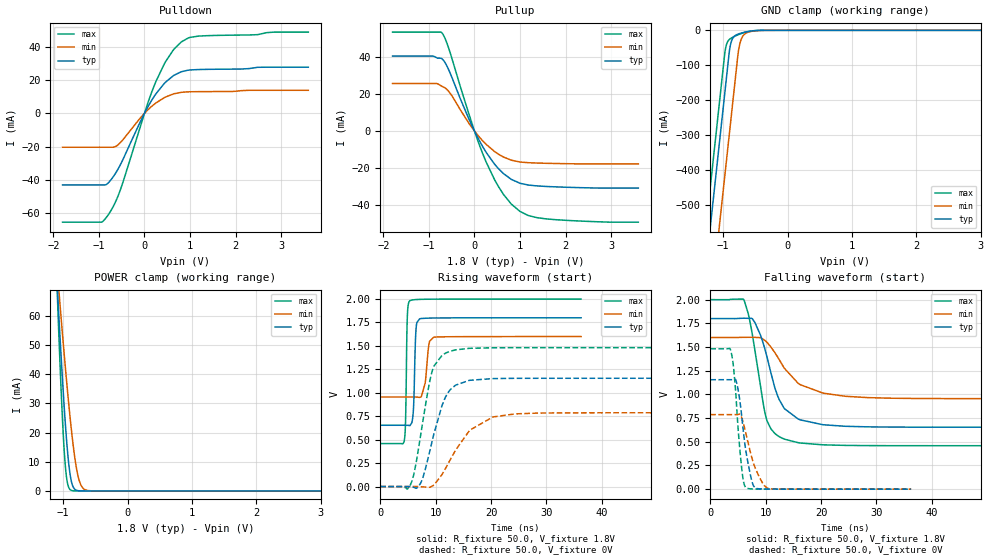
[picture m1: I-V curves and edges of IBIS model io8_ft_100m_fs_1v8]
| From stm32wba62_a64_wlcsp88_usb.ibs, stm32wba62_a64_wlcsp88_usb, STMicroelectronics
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[Model]   io8_ft_100m_fs_1v8
Model_type I/O
Polarity   Non-Inverting
Enable   Active-Low
| CAP_THRESHOLD on pad IOFT is "UDTCAPC" :
| Rising=30.0% of vddiom   Falling=70.0% of vddiom
| C_comp min and max val. don't necessarily correlate with the min and max pvt
| but are the smallest and greatest pad capacitance found.
| var   typ   min   max
C_comp   3.36302pF  3.33592pF  3.49657pF
|C_comp_pullup   1.98084pF  1.87511pF  2.12869pF
|C_comp_pulldown   1.38217pF  1.46081pF  1.36788pF
Vinl = 800.0mV
Vinh = 1.0V
Vmeas = 900.0mV   | Reference voltage for timing measurements
Cref  = 50.0pF   | Timing specification test load capacitance value
Rref  = 1.0MOhm   | Timing specification test load resistance value
Vref  = 990.0mV   | Timing specification test load voltage
[Model Spec]
| TIME_THRESHOLD on pin ZIV11 is "CMOS" :
| Rising=50.0% of vdd   Falling=50.0% of vdd
Vinl 702.50000mV 626.50000mV 788.50000mV
Vinh 1.09050V 959.50000mV 1.19650V
| variable   typ   min   max
[Temperature Range] 25.0 140.0 -40.0
| variable   typ   min   max
[Voltage Range] 1.8V 1.6V 2.0V
| variable   typ   min   max
[POWER Clamp Reference] 1.8V 1.6V 2.0V
| variable   typ   min   max
[GND Clamp Reference] 0V 0V 0V
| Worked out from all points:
|   slope of the pulldown table from 0 to 0.27 V, typ, clamps not added: 21.9 ohm
|   slope of the pullup table from 0 to 0.27 V, typ, clamps not added: 22.6 ohm
|   GND clamp passes 1 mA (typ) near -0.51 V on its own axis
|   POWER clamp passes 1 mA (typ) near -0.83 V on its own axis
|   rising waveform, R_fixture 50.0, V_fixture 1.8V: 20-80 % time 322ps typ, 667ps min, 236ps max; typ from 0.654 V to 1.8 V
|   falling waveform, R_fixture 50.0, V_fixture 1.8V: 20-80 % time 3.66ns typ, 5.8ns min, 2.61ns max; typ from 1.8 V to 0.654 V
|   rising waveform, R_fixture 50.0, V_fixture 0V: 20-80 % time 3.23ns typ, 5.55ns min, 2.57ns max; typ from 0 V to 1.16 V
|   falling waveform, R_fixture 50.0, V_fixture 0V: 20-80 % time 1.6ns typ, 2.36ns min, 1.18ns max; typ from 1.16 V to 0 V
[POWER Clamp]
-1.8V     396.4mA    285.5mA    556.9mA
-1.09V    69.42mA    75.17mA    67.14mA
-1.08V    65.31mA    72.42mA    61.23mA
-1.06V    57.23mA    66.98mA    49.77mA
-1.02V    41.75mA    56.3mA     28.91mA
-980mV    27.6mA     45.97mA    12.6mA
-940mV    15.59mA    36.11mA    3.485mA
-880mV    4.091mA    22.61mA    262.5uA
-820mV    594.6uA    11.56mA    16.39uA
-760mV    69.41uA    4.321mA    1.008uA
-630mV    611.2nA    197uA      2.486nA
3.6V      0A         0A         0A
[GND Clamp]
-1.8V     -1.583A    -1.82A     -1.468A
-1.43V    -953.9mA   -1.191A    -839.3mA
-1.24V    -630.9mA   -867.8mA   -516.3mA
-1.05V    -307.9mA   -544.8mA   -193.3mA
-980mV    -188.9mA   -425.8mA   -74.3mA
-950mV    -137.9mA   -374.8mA   -41.62mA
-890mV    -44.57mA   -272.8mA   -24.11mA
-800mV    -13.55mA   -119.8mA   -15.31mA
-760mV    -10.3mA    -56.67mA   -12.19mA
-720mV    -7.957mA   -26.08mA   -9.381mA
-540mV    -1.564mA   -2.435mA   -1.367mA
3.6V      1.281nA    268.1nA    531.2pA
| variable   typ   min   max
[Pullup Reference] 1.8V 1.6V 2.0V
| variable   typ   min   max
[Pulldown Reference] 0V 0V 0V
[Pullup]
-1.8V     40.39mA    25.65mA    53.35mA
-840mV    39.66mA    25.65mA    53.35mA
-700mV    38.63mA    23.9mA     52.42mA
-560mV    32.64mA    21.16mA    44.13mA
0V        593fA      222.5pA    3.42fA
260mV     -11.6mA    -7.233mA   -16.88mA
440mV     -17.8mA    -11.01mA   -26.16mA
630mV     -22.78mA   -13.92mA   -33.91mA
1V        -28.15mA   -16.69mA   -43.34mA
1.18V     -29.09mA   -17.06mA   -45.52mA
1.6V      -29.9mA    -17.4mA    -47.4mA
3.6V      -30.74mA   -17.73mA   -49.13mA
[Pulldown]
-1.8V     -42.97mA   -20.34mA   -65.35mA
-940mV    -42.97mA   -20.34mA   -65.31mA
-780mV    -41.3mA    -20.34mA   -60.25mA
-650mV    -36.58mA   -20.1mA    -53.93mA
-530mV    -30.86mA   -17.55mA   -45.89mA
0V        3fA        0A         0A
250mV     11.67mA    6.208mA    19.03mA
460mV     18.64mA    9.755mA    30.89mA
630mV     22.5mA     11.58mA    37.88mA
810mV     24.97mA    12.61mA    42.87mA
1.18V     26.28mA    13mA       46.33mA
3.6V      27.68mA    13.83mA    48.76mA
[Ramp]
dV/dt_r 693.11029mV/3.20165ns 472.14877mV/5.25042ns 888.79248mV/2.57222ns
dV/dt_f 687.69291mV/3.59389ns 386.8465mV/5.49572ns 924.86465mV/2.61188ns
R_load = 50.0
| Removed startup time: 0s 0s 0s  .
| Removed end time: 36.25ns.
[Rising Waveform]
R_fixture   = 50.0
V_fixture   = 1.8V
V_fixture_min = 1.6V
V_fixture_max = 2.0V
0s        653.8mV    955.3mV    458.6mV
4.3ns     653.9mV    955.3mV    481.6mV
4.55ns    653.9mV    955.3mV    668.4mV
4.9ns     653.6mV    955.3mV    1.837V
5.35ns    649.8mV    955.3mV    1.984V
6ns       837.6mV    955.2mV    1.992V
6.5ns     1.71V      954.8mV    1.995V
7.1ns     1.789V     950.8mV    1.996V
9.65ns    1.798V     1.593V     1.999V
36.25ns   1.8V       1.6V       2V
| Removed startup time: 0s 0s 0s  .
| Removed end time: 199.25ns.
[Falling Waveform]
R_fixture   = 50.0
V_fixture   = 1.8V
V_fixture_min = 1.6V
V_fixture_max = 2.0V
0s        1.8V       1.6V       2V
6.05ns    1.804V     1.603V     1.999V
6.95ns    1.803V     1.603V     1.828V
8ns       1.763V     1.602V     1.486V
9.65ns    1.52V      1.578V     873.3mV
10.3ns    1.38V      1.546V     713.1mV
12.5ns    938.3mV    1.361V     552.4mV
16.25ns   731.3mV    1.102V     487.1mV
32.55ns   655.3mV    959.9mV    459mV
199.3ns   653.8mV    955.3mV    458.6mV
| Removed startup time: 0s 0s 0s  .
| Removed end time: 199.2ns.
[Rising Waveform]
R_fixture   = 50.0
V_fixture   = 0V
V_fixture_min = 0V
V_fixture_max = 0V
0s        4.66nV     149.2nV    3.397nV
5.35ns    -1.172mV   471.1nV    8.191mV
6.15ns    -10.56mV   27.35uV    156.5mV
7.35ns    44.58mV    -1.872mV   571.2mV
9.5ns     518mV      9.132mV    1.255V
11.75ns   952.7mV    190.1mV    1.422V
13.6ns    1.082V     389.2mV    1.458V
16.25ns   1.134V     604.6mV    1.475V
24.4ns    1.154V     775.1mV    1.481V
199.2ns   1.155V     786.9mV    1.481V
| Removed startup time: 0s 0s 0s  .
| Removed end time: 36.25ns.
[Falling Waveform]
R_fixture   = 50.0
V_fixture   = 0V
V_fixture_min = 0V
V_fixture_max = 0V
0s        1.155V     786.9mV    1.481V
3.7ns     1.155V     786.9mV    1.461V
4.25ns    1.155V     786.9mV    1.257V
4.9ns     1.086V     787mV      741mV
5.75ns    729.5mV    740.9mV    180.6mV
6.4ns     411.6mV    595.6mV    18.08mV
7.8ns     34.99mV    272.6mV    1.972mV
9.65ns    1.899mV    41.61mV    774.7uV
10.35ns   1.345mV    9.299mV    644.6uV
36.25ns   1.594uV    7.4uV      677.6nV
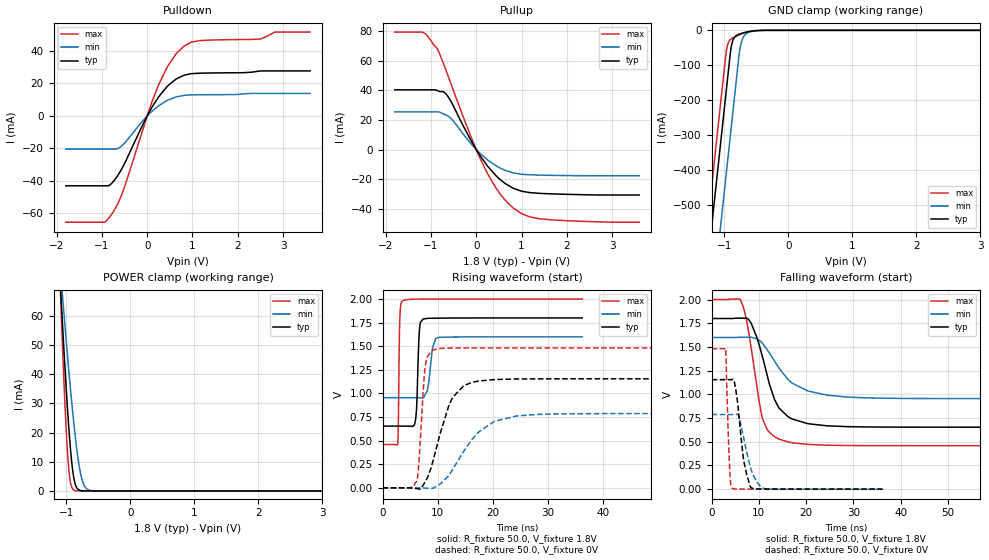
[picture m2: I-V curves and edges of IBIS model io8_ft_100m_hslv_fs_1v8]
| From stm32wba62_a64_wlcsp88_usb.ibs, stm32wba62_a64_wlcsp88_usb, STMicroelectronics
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[Model]   io8_ft_100m_hslv_fs_1v8
Model_type I/O
Polarity   Non-Inverting
Enable   Active-Low
| CAP_THRESHOLD on pad IOFT is "UDTCAPC" :
| Rising=30.0% of vddiom   Falling=70.0% of vddiom
| C_comp min and max val. don't necessarily correlate with the min and max pvt
| but are the smallest and greatest pad capacitance found.
| var   typ   min   max
C_comp   3.45851pF  3.43539pF  3.59268pF
|C_comp_pullup   2.05736pF  1.95438pF  2.20463pF
|C_comp_pulldown   1.40115pF  1.48101pF  1.38804pF
Vinl = 800.0mV
Vinh = 1.0V
Vmeas = 900.0mV   | Reference voltage for timing measurements
Cref  = 50.0pF   | Timing specification test load capacitance value
Rref  = 1.0MOhm   | Timing specification test load resistance value
Vref  = 990.0mV   | Timing specification test load voltage
[Model Spec]
| TIME_THRESHOLD on pin ZIV11 is "CMOS" :
| Rising=50.0% of vdd   Falling=50.0% of vdd
Vinl 702.50000mV 626.50000mV 788.50000mV
Vinh 1.09050V 959.50000mV 1.19650V
| variable   typ   min   max
[Temperature Range] 25.0 140.0 -40.0
| variable   typ   min   max
[Voltage Range] 1.8V 1.6V 2.0V
| variable   typ   min   max
[POWER Clamp Reference] 1.8V 1.6V 2.0V
| variable   typ   min   max
[GND Clamp Reference] 0V 0V 0V
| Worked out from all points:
|   slope of the pulldown table from 0 to 0.27 V, typ, clamps not added: 21.9 ohm
|   slope of the pullup table from 0 to 0.27 V, typ, clamps not added: 22.7 ohm
|   GND clamp passes 1 mA (typ) near -0.51 V on its own axis
|   POWER clamp passes 1 mA (typ) near -0.83 V on its own axis
|   rising waveform, R_fixture 50.0, V_fixture 1.8V: 20-80 % time 389ps typ, 756ps min, 202ps max; typ from 0.654 V to 1.8 V
|   falling waveform, R_fixture 50.0, V_fixture 1.8V: 20-80 % time 4.19ns typ, 6.65ns min, 2.95ns max; typ from 1.8 V to 0.654 V
|   rising waveform, R_fixture 50.0, V_fixture 0V: 20-80 % time 3.54ns typ, 6.08ns min, 949ps max; typ from 0 V to 1.16 V
|   falling waveform, R_fixture 50.0, V_fixture 0V: 20-80 % time 1.62ns typ, 2.33ns min, 588ps max; typ from 1.16 V to 0 V
[POWER Clamp]
-1.8V     396.4mA    285.5mA    556.9mA
-1.09V    69.42mA    75.17mA    67.14mA
-1.08V    65.31mA    72.42mA    61.23mA
-1.06V    57.23mA    66.98mA    49.77mA
-1.02V    41.75mA    56.3mA     28.91mA
-980mV    27.6mA     45.97mA    12.6mA
-940mV    15.59mA    36.11mA    3.485mA
-880mV    4.091mA    22.61mA    262.5uA
-820mV    594.6uA    11.56mA    16.39uA
-760mV    69.41uA    4.321mA    1.008uA
-630mV    611.3nA    197uA      2.478nA
3.6V      0A         0A         0A
[GND Clamp]
-1.8V     -1.583A    -1.82A     -1.468A
-1.43V    -953.9mA   -1.191A    -839.3mA
-1.24V    -630.9mA   -867.8mA   -516.3mA
-1.05V    -307.9mA   -544.8mA   -193.3mA
-980mV    -188.9mA   -425.8mA   -74.3mA
-950mV    -137.9mA   -374.8mA   -41.62mA
-890mV    -44.57mA   -272.8mA   -24.11mA
-800mV    -13.55mA   -119.8mA   -15.31mA
-760mV    -10.3mA    -56.67mA   -12.19mA
-720mV    -7.957mA   -26.08mA   -9.381mA
-540mV    -1.564mA   -2.435mA   -1.367mA
3.6V      1.279nA    269.1nA    528.1pA
| variable   typ   min   max
[Pullup Reference] 1.8V 1.6V 2.0V
| variable   typ   min   max
[Pulldown Reference] 0V 0V 0V
[Pullup]
-1.8V     40.42mA    25.47mA    79.48mA
-1.18V    40.42mA    25.47mA    79.3mA
-860mV    39.94mA    25.47mA    68.19mA
-710mV    38.81mA    23.9mA     57mA
-620mV    35.69mA    22.65mA    49.65mA
-310mV    17.32mA    11.4mA     23.88mA
70mV      -3.436mA   -2.157mA   -4.962mA
440mV     -17.8mA    -11.01mA   -26.16mA
810mV     -26.07mA   -15.71mA   -39.4mA
1V        -28.15mA   -16.69mA   -43.34mA
1.37V     -29.57mA   -17.25mA   -46.68mA
3.6V      -30.74mA   -17.73mA   -49.13mA
[Pulldown]
-1.8V     -42.97mA   -20.34mA   -65.35mA
-940mV    -42.97mA   -20.34mA   -65.31mA
-780mV    -41.3mA    -20.34mA   -60.25mA
-530mV    -30.86mA   -17.55mA   -45.89mA
0V        0A         -230fA     0A
250mV     11.67mA    6.208mA    19.03mA
460mV     18.64mA    9.755mA    30.89mA
810mV     24.97mA    12.61mA    42.87mA
1.18V     26.28mA    13mA       46.33mA
2.49V     27.61mA    13.8mA     47.25mA
2.83V     27.66mA    13.8mA     51.53mA
3.6V      27.66mA    13.8mA     51.53mA
[Ramp]
dV/dt_r 693.10773mV/3.51841ns 472.14152mV/5.83471ns 888.79301mV/947.57443ps
dV/dt_f 687.69292mV/4.12664ns 386.84547mV/6.35604ns 924.86466mV/2.94887ns
R_load = 50.0
| Removed startup time: 0s 0s 0s  .
| Removed end time: 36.25ns.
[Rising Waveform]
R_fixture   = 50.0
V_fixture   = 1.8V
V_fixture_min = 1.6V
V_fixture_max = 2.0V
0s        653.8mV    955.3mV    458.6mV
2.75ns    653.8mV    955.2mV    471.2mV
2.85ns    653.8mV    955.3mV    614.9mV
3.15ns    653.9mV    955.3mV    1.817V
3.7ns     653.8mV    955.3mV    1.984V
5.9ns     692.6mV    955.3mV    1.999V
6.7ns     1.673V     954.7mV    2V
7.35ns    1.788V     951.1mV    2V
9.65ns    1.797V     1.583V     2V
36.25ns   1.8V       1.6V       2V
| Removed startup time: 0s 0s 0s  .
| Removed end time: 199.25ns.
[Falling Waveform]
R_fixture   = 50.0
V_fixture   = 1.8V
V_fixture_min = 1.6V
V_fixture_max = 2.0V
0s        1.8V       1.6V       2V
6.15ns    1.804V     1.603V     1.993V
7.1ns     1.802V     1.603V     1.849V
8.4ns     1.747V     1.602V     1.484V
10.85ns   1.381V     1.533V     735.2mV
13.35ns   942.7mV    1.35V      552.6mV
17.1ns    739mV      1.117V     489.2mV
24.4ns    668.4mV    991.8mV    463.6mV
36.6ns    654.8mV    959mV      458.8mV
199.3ns   653.8mV    955.3mV    458.6mV
| Removed startup time: 0s 0s 0s  .
| Removed end time: 199.25ns.
[Rising Waveform]
R_fixture   = 50.0
V_fixture   = 0V
V_fixture_min = 0V
V_fixture_max = 0V
0s        4.612nV    149.7nV    3.356nV
6.2ns     -7.548mV   18.85uV    68.67mV
6.55ns    -11.29mV   78.32uV    231.8mV
7.8ns     72.77mV    -3.108mV   1.306V
10.45ns   573.8mV    39.73mV    1.478V
12.7ns    956.5mV    191.6mV    1.481V
14.75ns   1.083V     389.9mV    1.481V
20.35ns   1.147V     706.6mV    1.481V
28.45ns   1.155V     778.5mV    1.481V
199.3ns   1.155V     786.9mV    1.481V
| Removed startup time: 0s 0s 0s  .
| Removed end time: 36.2ns.
[Falling Waveform]
R_fixture   = 50.0
V_fixture   = 0V
V_fixture_min = 0V
V_fixture_max = 0V
0s        1.155V     786.9mV    1.481V
2.95ns    1.155V     786.9mV    1.484V
3.75ns    1.155V     786.9mV    299.7mV
4.3ns     1.155V     787mV      10.97mV
4.85ns    1.126V     786.7mV    2.667mV
5.65ns    846.5mV    780.7mV    1.393mV
6.85ns    291.5mV    527.9mV    598.2uV
8.4ns     13.55mV    200.7mV    216.8uV
11.1ns    1.16mV     5.941mV    46.76uV
36.2ns    3.118uV    12.69uV    -7.202nV
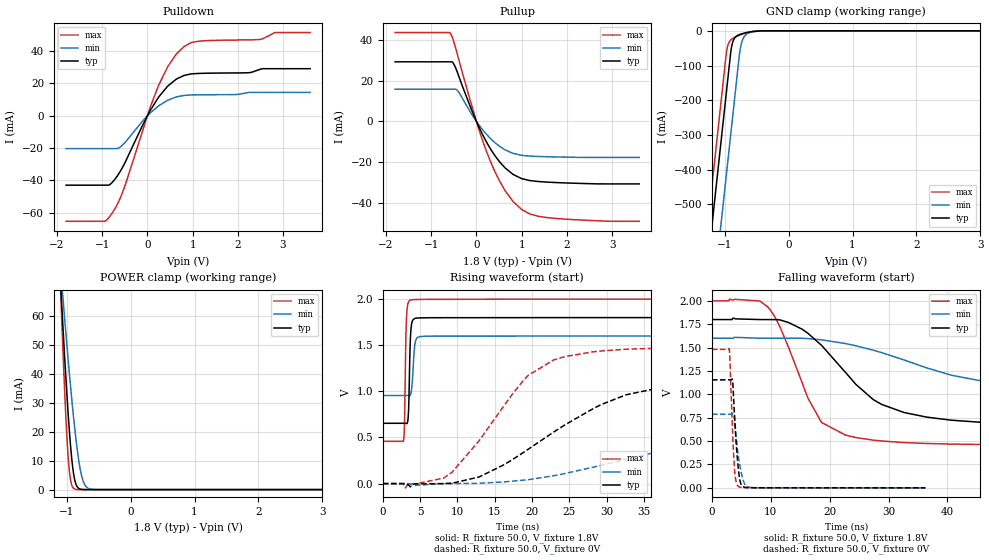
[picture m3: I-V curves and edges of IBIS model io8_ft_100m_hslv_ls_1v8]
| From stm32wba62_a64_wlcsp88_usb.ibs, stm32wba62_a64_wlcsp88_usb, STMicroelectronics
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[Model]   io8_ft_100m_hslv_ls_1v8
Model_type I/O
Polarity   Non-Inverting
Enable   Active-Low
| CAP_THRESHOLD on pad IOFT is "UDTCAPC" :
| Rising=30.0% of vddiom   Falling=70.0% of vddiom
| C_comp min and max val. don't necessarily correlate with the min and max pvt
| but are the smallest and greatest pad capacitance found.
| var   typ   min   max
C_comp   3.45875pF  3.43496pF  3.59275pF
|C_comp_pullup   2.05726pF  1.95366pF  2.20456pF
|C_comp_pulldown   1.40149pF  1.48130pF  1.38819pF
Vinl = 800.0mV
Vinh = 1.0V
Vmeas = 900.0mV   | Reference voltage for timing measurements
Cref  = 50.0pF   | Timing specification test load capacitance value
Rref  = 1.0MOhm   | Timing specification test load resistance value
Vref  = 990.0mV   | Timing specification test load voltage
[Model Spec]
| TIME_THRESHOLD on pin ZIV11 is "CMOS" :
| Rising=50.0% of vdd   Falling=50.0% of vdd
Vinl 702.50000mV 626.50000mV 788.50000mV
Vinh 1.09050V 959.50000mV 1.19650V
| variable   typ   min   max
[Temperature Range] 25.0 140.0 -40.0
| variable   typ   min   max
[Voltage Range] 1.8V 1.6V 2.0V
| variable   typ   min   max
[POWER Clamp Reference] 1.8V 1.6V 2.0V
| variable   typ   min   max
[GND Clamp Reference] 0V 0V 0V
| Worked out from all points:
|   slope of the pulldown table from 0 to 0.27 V, typ, clamps not added: 21.9 ohm
|   slope of the pullup table from 0 to 0.27 V, typ, clamps not added: 22.5 ohm
|   GND clamp passes 1 mA (typ) near -0.51 V on its own axis
|   POWER clamp passes 1 mA (typ) near -0.83 V on its own axis
|   rising waveform, R_fixture 50.0, V_fixture 1.8V: 20-80 % time 209ps typ, 316ps min, 197ps max; typ from 0.654 V to 1.8 V
|   falling waveform, R_fixture 50.0, V_fixture 1.8V: 20-80 % time 11.5ns typ, 25.3ns min, 6.25ns max; typ from 1.8 V to 0.654 V
|   rising waveform, R_fixture 50.0, V_fixture 0V: 20-80 % time 14.6ns typ, 29.3ns min, 8.6ns max; typ from 0 V to 1.16 V
|   falling waveform, R_fixture 50.0, V_fixture 0V: 20-80 % time 736ps typ, 1.01ns min, 581ps max; typ from 1.16 V to 0 V
[POWER Clamp]
-1.8V     396.4mA    285.5mA    556.9mA
-1.09V    69.42mA    75.17mA    67.14mA
-1.08V    65.31mA    72.42mA    61.23mA
-1.06V    57.23mA    66.98mA    49.77mA
-1.02V    41.75mA    56.3mA     28.91mA
-980mV    27.6mA     45.97mA    12.6mA
-940mV    15.59mA    36.11mA    3.485mA
-880mV    4.091mA    22.61mA    262.5uA
-820mV    594.6uA    11.56mA    16.39uA
-760mV    69.41uA    4.321mA    1.008uA
-630mV    611.2nA    197uA      2.478nA
3.6V      0A         0A         0A
[GND Clamp]
-1.8V     -1.583A    -1.82A     -1.468A
-1.43V    -953.9mA   -1.191A    -839.3mA
-1.24V    -630.9mA   -867.8mA   -516.3mA
-1.05V    -307.9mA   -544.8mA   -193.3mA
-980mV    -188.9mA   -425.8mA   -74.3mA
-950mV    -137.9mA   -374.8mA   -41.62mA
-890mV    -44.57mA   -272.8mA   -24.11mA
-800mV    -13.55mA   -119.8mA   -15.31mA
-760mV    -10.3mA    -56.67mA   -12.19mA
-720mV    -7.957mA   -26.08mA   -9.381mA
-540mV    -1.564mA   -2.435mA   -1.367mA
3.6V      1.279nA    269.1nA    528.1pA
| variable   typ   min   max
[Pullup Reference] 1.8V 1.6V 2.0V
| variable   typ   min   max
[Pulldown Reference] 0V 0V 0V
[Pullup]
-1.8V     29.32mA    15.84mA    43.71mA
-580mV    29.32mA    15.84mA    43.43mA
-510mV    28.58mA    15.84mA    39.84mA
-410mV    23.44mA    14.96mA    32.05mA
10mV      -505.3uA   -317.7uA   -727.9uA
290mV     -12.73mA   -7.931mA   -18.57mA
440mV     -17.8mA    -11.01mA   -26.16mA
640mV     -23mA      -14.05mA   -34.26mA
1V        -28.15mA   -16.69mA   -43.34mA
1.18V     -29.09mA   -17.06mA   -45.51mA
1.6V      -29.9mA    -17.4mA    -47.4mA
3.6V      -30.74mA   -17.72mA   -49.13mA
[Pulldown]
-1.8V     -42.97mA   -20.34mA   -65.35mA
-940mV    -42.97mA   -20.34mA   -65.31mA
-780mV    -41.3mA    -20.34mA   -60.25mA
-530mV    -30.86mA   -17.55mA   -45.89mA
0V        3.81fA     -960fA     -3.4fA
250mV     11.67mA    6.207mA    19.03mA
460mV     18.64mA    9.753mA    30.89mA
810mV     24.97mA    12.6mA     42.87mA
1.18V     26.28mA    13mA       46.33mA
2.49V     28.73mA    14.48mA    47.25mA
2.83V     29.16mA    14.48mA    51.53mA
3.6V      29.16mA    14.48mA    51.53mA
[Ramp]
dV/dt_r 693.10179mV/14.42876ns 472.07131mV/29.21331ns 888.79124mV/8.331ns
dV/dt_f 687.69237mV/11.28365ns 386.78917mV/24.82773ns 924.86462mV/5.99237ns
R_load = 50.0
| Removed startup time: 0s 0s 0s  .
| Removed end time: 36.25ns.
[Rising Waveform]
R_fixture   = 50.0
V_fixture   = 1.8V
V_fixture_min = 1.6V
V_fixture_max = 2.0V
0s        653.8mV    955.4mV    458.6mV
2.8ns     653.7mV    955.3mV    477mV
2.9ns     653.9mV    955.3mV    645.5mV
3.15ns    651.4mV    955.4mV    1.761V
3.45ns    795.7mV    953.6mV    1.971V
3.65ns    1.483V     953.6mV    1.988V
3.85ns    1.728V     1.02V      1.993V
4.3ns     1.79V      1.509V     1.995V
4.9ns     1.796V     1.593V     1.996V
36.25ns   1.8V       1.6V       2V
| Removed startup time: 0s 0s 0s  .
| Removed end time: 399.25ns.
[Falling Waveform]
R_fixture   = 50.0
V_fixture   = 1.8V
V_fixture_min = 1.6V
V_fixture_max = 2.0V
0s        1.8V       1.6V       2V
9.65ns    1.8V       1.6V       1.924V
13.05ns   1.768V     1.6V       1.499V
16.3ns    1.654V     1.597V     961.3mV
18.6ns    1.526V     1.584V     700.1mV
27.4ns    944.2mV    1.473V     510.4mV
32.6ns    806.5mV    1.368V     484.5mV
48.9ns    688.7mV    1.11V      462.3mV
89.65ns   655.5mV    977.7mV    458.6mV
399.3ns   653.8mV    955.4mV    458.6mV
| Removed startup time: 0s 0s 0s  .
| Removed end time: 399.2ns.
[Rising Waveform]
R_fixture   = 50.0
V_fixture   = 0V
V_fixture_min = 0V
V_fixture_max = 0V
0s        4.614nV    149.8nV    3.359nV
3.05ns    200.7uV    -78.92uV   -46.11mV
9.3ns     4.754mV    -211.5uV   125.2mV
18.8ns    335.2mV    36.98mV    1.115V
22.9ns    559mV      85.48mV    1.341V
32.6ns    962.7mV    263.9mV    1.457V
40.75ns   1.086V     417.8mV    1.475V
57.05ns   1.143V     636.3mV    1.481V
89.65ns   1.155V     766.5mV    1.481V
399.2ns   1.155V     786.8mV    1.481V
| Removed startup time: 0s 0s 0s  .
| Removed end time: 36.25ns.
[Falling Waveform]
R_fixture   = 50.0
V_fixture   = 0V
V_fixture_min = 0V
V_fixture_max = 0V
0s        1.155V     786.9mV    1.481V
2.95ns    1.155V     787mV      1.487V
3.05ns    1.155V     787.1mV    1.403V
3.5ns     1.156V     789.4mV    628.3mV
3.8ns     824.8mV    763.5mV    242.8mV
4.1ns     502.6mV    562mV      70.17mV
4.55ns    174.8mV    315mV      13.54mV
5.5ns     7.412mV    50.22mV    2.417mV
6.65ns    1.558mV    3.188mV    1.758mV
36.25ns   96.44uV    186.6uV    38.67uV
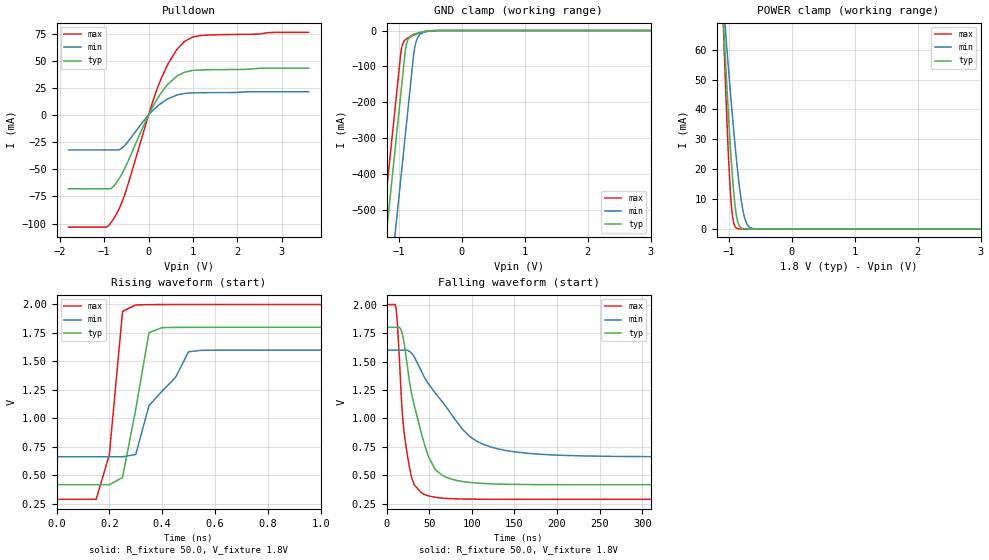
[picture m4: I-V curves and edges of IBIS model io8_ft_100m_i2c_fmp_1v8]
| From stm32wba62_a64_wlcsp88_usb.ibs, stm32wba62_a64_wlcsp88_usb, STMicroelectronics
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[Model]   io8_ft_100m_i2c_fmp_1v8
Model_type I/O_open_drain
Polarity   Non-Inverting
Enable   Active-Low
| CAP_THRESHOLD on pad IOFT is "UDTCAPC" :
| Rising=30.0% of vddiom   Falling=70.0% of vddiom
| C_comp min and max val. don't necessarily correlate with the min and max pvt
| but are the smallest and greatest pad capacitance found.
| var   typ   min   max
C_comp   3.34888pF  3.31958pF  3.48457pF
|C_comp_pulldown   3.34888pF  3.31958pF  3.48457pF
Vinl = 800.0mV
Vinh = 1.0V
Vmeas = 900.0mV   | Reference voltage for timing measurements
Cref  = 50.0pF   | Timing specification test load capacitance value
Rref  = 1.0MOhm   | Timing specification test load resistance value
Vref  = 990.0mV   | Timing specification test load voltage
[Model Spec]
| TIME_THRESHOLD on pin ZII2CV11 is "CMOS" :
| Rising=50.0% of vdd   Falling=50.0% of vdd
Vinl 702.50000mV 626.50000mV 788.50000mV
Vinh 1.09050V 959.50000mV 1.19650V
| variable   typ   min   max
[Temperature Range] 25.0 140.0 -40.0
| variable   typ   min   max
[Voltage Range] 1.8V 1.6V 2.0V
| variable   typ   min   max
[POWER Clamp Reference] 1.8V 1.6V 2.0V
| variable   typ   min   max
[GND Clamp Reference] 0V 0V 0V
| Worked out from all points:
|   slope of the pulldown table from 0 to 0.27 V, typ, clamps not added: 13.7 ohm
|   GND clamp passes 1 mA (typ) near -0.51 V on its own axis
|   POWER clamp passes 1 mA (typ) near -0.83 V on its own axis
|   rising waveform, R_fixture 50.0, V_fixture 1.8V: 20-80 % time 65.2ps typ, 142ps min, 45.2ps max; typ from 0.419 V to 1.8 V
|   falling waveform, R_fixture 50.0, V_fixture 1.8V: 20-80 % time 24.6ns typ, 55.3ns min, 11.4ns max; typ from 1.8 V to 0.419 V
[POWER Clamp]
-1.8V     396.4mA    285.5mA    556.9mA
-1.09V    69.42mA    75.17mA    67.14mA
-1.08V    65.31mA    72.42mA    61.23mA
-1.06V    57.23mA    66.98mA    49.77mA
-1.02V    41.75mA    56.3mA     28.91mA
-980mV    27.6mA     45.97mA    12.6mA
-940mV    15.59mA    36.11mA    3.485mA
-880mV    4.091mA    22.61mA    262.5uA
-820mV    594.6uA    11.56mA    16.39uA
-760mV    69.41uA    4.321mA    1.008uA
-630mV    611.2nA    197uA      2.486nA
3.6V      0A         0A         0A
[GND Clamp]
-1.8V     -1.583A    -1.82A     -1.468A
-1.43V    -953.9mA   -1.191A    -839.3mA
-1.24V    -630.9mA   -867.8mA   -516.3mA
-1.05V    -307.9mA   -544.8mA   -193.3mA
-980mV    -188.9mA   -425.8mA   -74.3mA
-950mV    -137.9mA   -374.8mA   -41.62mA
-890mV    -44.57mA   -272.8mA   -24.11mA
-800mV    -13.55mA   -119.8mA   -15.31mA
-760mV    -10.3mA    -56.67mA   -12.19mA
-720mV    -7.957mA   -26.08mA   -9.381mA
-540mV    -1.564mA   -2.435mA   -1.367mA
3.6V      1.281nA    268.1nA    531.2pA
| variable   typ   min   max
[Pullup Reference] 1.8V 1.6V 2.0V
| variable   typ   min   max
[Pulldown Reference] 0V 0V 0V
[Pulldown]
-1.8V     -67.91mA   -32.13mA   -103.3mA
-940mV    -67.91mA   -32.13mA   -103.2mA
-780mV    -65.26mA   -32.13mA   -95.24mA
-650mV    -57.81mA   -31.76mA   -85.25mA
-530mV    -48.77mA   -27.72mA   -72.55mA
0V        0A         -20fA      3fA
250mV     18.45mA    9.809mA    30.09mA
440mV     28.58mA    14.98mA    47.3mA
630mV     35.56mA    18.31mA    59.9mA
810mV     39.48mA    19.92mA    67.8mA
1.18V     41.55mA    20.55mA    73.29mA
3.6V      43.15mA    21.44mA    76.19mA
[Ramp]
dV/dt_r 828.63291mV/1.41298ns 561.65308mV/2.60096ns 1.02558V/815.67609ps
dV/dt_f 828.65387mV/24.39736ns 561.54878mV/55.07705ns 1.02559V/11.30948ns
R_load = 50.0
| Removed startup time: 0s 0s 0s  .
| Removed end time: 1.75ns.
[Rising Waveform]
R_fixture   = 50.0
V_fixture   = 1.8V
V_fixture_min = 1.6V
V_fixture_max = 2.0V
0s        418.9mV    663.9mV    290.7mV
150ps     418.9mV    663.9mV    290.7mV
200ps     418.9mV    663.8mV    682.6mV
250ps     482.7mV    663.8mV    1.939V
300ps     1.081V     684.1mV    1.996V
350ps     1.753V     1.112V     1.999V
400ps     1.797V     1.241V     1.999V
450ps     1.799V     1.359V     2V
500ps     1.799V     1.585V     2V
1.75ns    1.8V       1.6V       2V
| Removed startup time: 0s 0s 0s  .
| Removed end time: 399.25ns.
[Falling Waveform]
R_fixture   = 50.0
V_fixture   = 1.8V
V_fixture_min = 1.6V
V_fixture_max = 2.0V
0s        1.8V       1.6V       2V
10.95ns   1.8V       1.6V       1.971V
20.9ns    1.648V     1.6V       861.1mV
30ns      1.199V     1.567V     468.7mV
40.75ns   873.6mV    1.418V     348.3mV
48.9ns    668.9mV    1.307V     321.3mV
65.2ns    502.3mV    1.148V     301.3mV
97.8ns    438.8mV    840.6mV    292.2mV
122.2ns   426.8mV    750.1mV    291.1mV
399.3ns   418.9mV    664.1mV    290.7mV
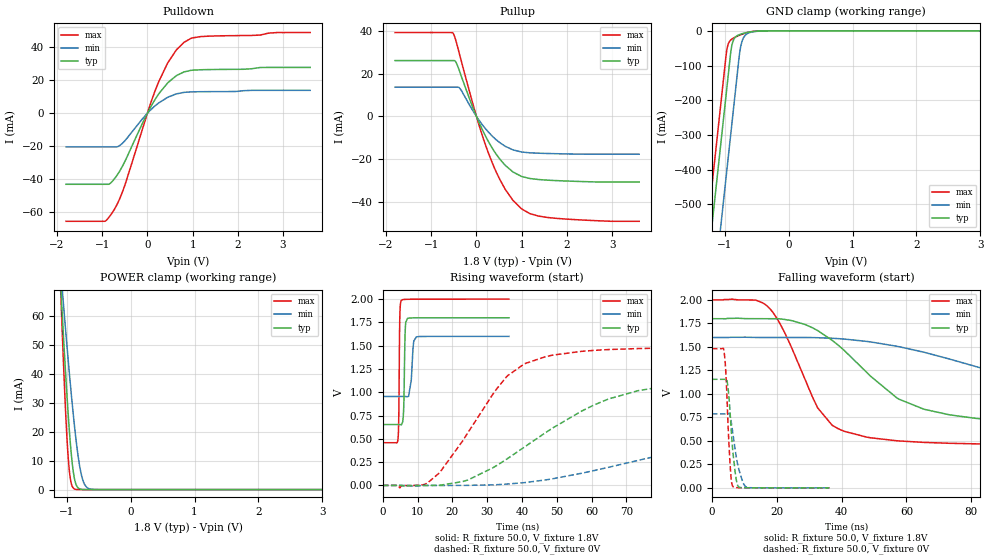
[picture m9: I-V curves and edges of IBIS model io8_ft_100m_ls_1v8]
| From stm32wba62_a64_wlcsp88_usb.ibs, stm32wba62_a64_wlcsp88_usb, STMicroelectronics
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[Model]   io8_ft_100m_ls_1v8
Model_type I/O
Polarity   Non-Inverting
Enable   Active-Low
| CAP_THRESHOLD on pad IOFT is "UDTCAPC" :
| Rising=30.0% of vddiom   Falling=70.0% of vddiom
| C_comp min and max val. don't necessarily correlate with the min and max pvt
| but are the smallest and greatest pad capacitance found.
| var   typ   min   max
C_comp   3.36302pF  3.33592pF  3.49657pF
|C_comp_pullup   1.98052pF  1.87479pF  2.12836pF
|C_comp_pulldown   1.38250pF  1.46113pF  1.36821pF
Vinl = 800.0mV
Vinh = 1.0V
Vmeas = 900.0mV   | Reference voltage for timing measurements
Cref  = 50.0pF   | Timing specification test load capacitance value
Rref  = 1.0MOhm   | Timing specification test load resistance value
Vref  = 990.0mV   | Timing specification test load voltage
[Model Spec]
| TIME_THRESHOLD on pin ZIV11 is "CMOS" :
| Rising=50.0% of vdd   Falling=50.0% of vdd
Vinl 702.50000mV 626.50000mV 788.50000mV
Vinh 1.09050V 959.50000mV 1.19650V
| variable   typ   min   max
[Temperature Range] 25.0 140.0 -40.0
| variable   typ   min   max
[Voltage Range] 1.8V 1.6V 2.0V
| variable   typ   min   max
[POWER Clamp Reference] 1.8V 1.6V 2.0V
| variable   typ   min   max
[GND Clamp Reference] 0V 0V 0V
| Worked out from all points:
|   slope of the pulldown table from 0 to 0.27 V, typ, clamps not added: 21.9 ohm
|   slope of the pullup table from 0 to 0.27 V, typ, clamps not added: 22.5 ohm
|   GND clamp passes 1 mA (typ) near -0.51 V on its own axis
|   POWER clamp passes 1 mA (typ) near -0.83 V on its own axis
|   rising waveform, R_fixture 50.0, V_fixture 1.8V: 20-80 % time 320ps typ, 710ps min, 235ps max; typ from 0.654 V to 1.8 V
|   falling waveform, R_fixture 50.0, V_fixture 1.8V: 20-80 % time 25ns typ, 55.5ns min, 12.8ns max; typ from 1.8 V to 0.654 V
|   rising waveform, R_fixture 50.0, V_fixture 0V: 20-80 % time 31.2ns typ, 66.6ns min, 16.7ns max; typ from 0 V to 1.16 V
|   falling waveform, R_fixture 50.0, V_fixture 0V: 20-80 % time 1.6ns typ, 2.38ns min, 1.18ns max; typ from 1.16 V to 0 V
[POWER Clamp]
-1.8V     396.4mA    285.5mA    556.9mA
-1.09V    69.42mA    75.17mA    67.14mA
-1.08V    65.31mA    72.42mA    61.23mA
-1.06V    57.23mA    66.98mA    49.77mA
-1.02V    41.75mA    56.3mA     28.91mA
-980mV    27.6mA     45.97mA    12.6mA
-940mV    15.59mA    36.11mA    3.485mA
-880mV    4.091mA    22.61mA    262.5uA
-820mV    594.6uA    11.56mA    16.39uA
-760mV    69.41uA    4.321mA    1.008uA
-630mV    611.2nA    197uA      2.486nA
3.6V      0A         0A         0A
[GND Clamp]
-1.8V     -1.583A    -1.82A     -1.468A
-1.43V    -953.9mA   -1.191A    -839.3mA
-1.24V    -630.9mA   -867.8mA   -516.3mA
-1.05V    -307.9mA   -544.8mA   -193.3mA
-980mV    -188.9mA   -425.8mA   -74.3mA
-950mV    -137.9mA   -374.8mA   -41.62mA
-890mV    -44.57mA   -272.8mA   -24.11mA
-800mV    -13.55mA   -119.8mA   -15.31mA
-760mV    -10.3mA    -56.67mA   -12.19mA
-720mV    -7.957mA   -26.08mA   -9.381mA
-540mV    -1.564mA   -2.435mA   -1.367mA
3.6V      1.281nA    268.1nA    531.2pA
| variable   typ   min   max
[Pullup Reference] 1.8V 1.6V 2.0V
| variable   typ   min   max
[Pulldown Reference] 0V 0V 0V
[Pullup]
-1.8V     26.12mA    13.66mA    39.23mA
-520mV    26.12mA    13.66mA    39.04mA
-460mV    25.58mA    13.66mA    35.85mA
-360mV    20.34mA    12.93mA    27.94mA
30mV      -1.501mA   -943.7uA   -2.165mA
310mV     -13.47mA   -8.382mA   -19.66mA
640mV     -23mA      -14.05mA   -34.26mA
810mV     -26.07mA   -15.71mA   -39.4mA
1V        -28.15mA   -16.69mA   -43.34mA
1.18V     -29.09mA   -17.06mA   -45.52mA
1.6V      -29.9mA    -17.4mA    -47.4mA
3.6V      -30.74mA   -17.73mA   -49.13mA
[Pulldown]
-1.8V     -42.97mA   -20.34mA   -65.35mA
-940mV    -42.97mA   -20.34mA   -65.31mA
-780mV    -41.3mA    -20.34mA   -60.25mA
-650mV    -36.58mA   -20.1mA    -53.93mA
-530mV    -30.86mA   -17.55mA   -45.89mA
0V        0A         -20fA      -1.8fA
250mV     11.67mA    6.208mA    19.03mA
460mV     18.64mA    9.755mA    30.89mA
630mV     22.5mA     11.58mA    37.88mA
810mV     24.97mA    12.61mA    42.87mA
1.18V     26.28mA    13mA       46.33mA
3.6V      27.68mA    13.83mA    48.76mA
[Ramp]
dV/dt_r 693.09206mV/31.17277ns 471.98968mV/66.37777ns 888.78873mV/16.37787ns
dV/dt_f 687.69346mV/24.39611ns 386.64306mV/55.12311ns 924.86461mV/12.22519ns
R_load = 50.0
| Removed startup time: 0s 0s 0s  .
| Removed end time: 36.25ns.
[Rising Waveform]
R_fixture   = 50.0
V_fixture   = 1.8V
V_fixture_min = 1.6V
V_fixture_max = 2.0V
0s        653.8mV    955.3mV    458.6mV
4.3ns     653.9mV    955.3mV    482.2mV
4.55ns    653.9mV    955.3mV    668.3mV
4.9ns     653.6mV    955.3mV    1.841V
5.35ns    650.5mV    955.3mV    1.988V
6ns       837.4mV    955.3mV    1.996V
6.5ns     1.713V     954.7mV    1.997V
7.1ns     1.793V     951.4mV    1.998V
9.65ns    1.799V     1.595V     1.999V
36.25ns   1.8V       1.6V       2V
| Removed startup time: 0s 0s 0s  .
| Removed end time: 399.25ns.
[Falling Waveform]
R_fixture   = 50.0
V_fixture   = 1.8V
V_fixture_min = 1.6V
V_fixture_max = 2.0V
0s        1.8V       1.6V       2V
16.55ns   1.8V       1.6V       1.949V
22.45ns   1.792V     1.6V       1.652V
32.6ns    1.674V     1.598V     852mV
37.1ns    1.57V      1.592V     666mV
57.05ns   956.8mV    1.507V     501.1mV
81.5ns    739.1mV    1.29V      468.5mV
106ns     685.8mV    1.125V     461.2mV
138.6ns   663.7mV    1.034V     459mV
399.3ns   653.8mV    955.6mV    458.6mV
| Removed startup time: 0s 0s 0s  .
| Removed end time: 399.2ns.
[Rising Waveform]
R_fixture   = 50.0
V_fixture   = 0V
V_fixture_min = 0V
V_fixture_max = 0V
0s        4.66nV     149.2nV    3.397nV
12.85ns   -301.7uV   -158.7uV   27.01mV
24.45ns   58.1mV     866uV      566.3mV
35.9ns    289.7mV    15.4mV     1.179V
46.85ns   568.8mV    59.56mV    1.383V
57.05ns   796.2mV    130.2mV    1.439V
73.35ns   1.017V     268.5mV    1.469V
87.5ns    1.091V     388.4mV    1.477V
154.8ns   1.152V     713.2mV    1.481V
399.2ns   1.155V     786.6mV    1.481V
| Removed startup time: 0s 0s 0s  .
| Removed end time: 36.25ns.
[Falling Waveform]
R_fixture   = 50.0
V_fixture   = 0V
V_fixture_min = 0V
V_fixture_max = 0V
0s        1.155V     786.9mV    1.481V
3.65ns    1.155V     786.9mV    1.472V
4.25ns    1.155V     786.9mV    1.259V
4.9ns     1.088V     787mV      743.2mV
5.75ns    733mV      743.3mV    181.4mV
6.05ns    574mV      682.1mV    67.41mV
6.4ns     413.9mV    598.8mV    18.47mV
7.8ns     38.76mV    274.9mV    2.057mV
10.35ns   1.122mV    12.57mV    791.6uV
36.25ns   215.5uV    163.4uV    117.2uV
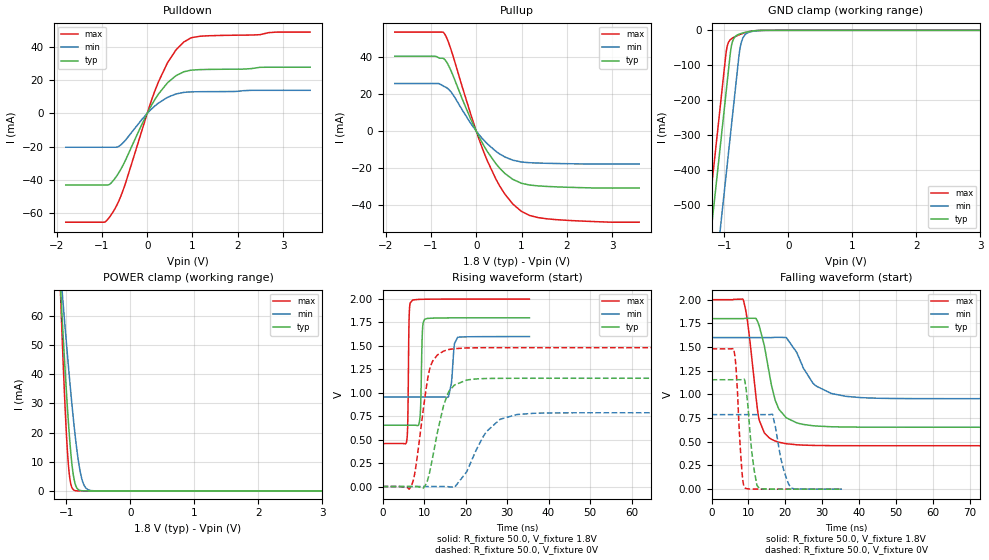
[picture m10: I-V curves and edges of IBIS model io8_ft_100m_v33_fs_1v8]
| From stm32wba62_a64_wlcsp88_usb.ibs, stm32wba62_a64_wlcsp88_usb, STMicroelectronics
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[Model]   io8_ft_100m_v33_fs_1v8
Model_type I/O
Polarity   Non-Inverting
Enable   Active-Low
| CAP_THRESHOLD on pad IOFT is "UDTCAPC" :
| Rising=30.0% of vddiom   Falling=70.0% of vddiom
| C_comp min and max val. don't necessarily correlate with the min and max pvt
| but are the smallest and greatest pad capacitance found.
| var   typ   min   max
C_comp   3.44267pF  3.41636pF  3.57935pF
|C_comp_pullup   2.04612pF  1.94137pF  2.19279pF
|C_comp_pulldown   1.39655pF  1.47499pF  1.38656pF
Vinl = 800.0mV
Vinh = 1.0V
Vmeas = 900.0mV   | Reference voltage for timing measurements
Cref  = 50.0pF   | Timing specification test load capacitance value
Rref  = 1.0MOhm   | Timing specification test load resistance value
Vref  = 990.0mV   | Timing specification test load voltage
[Model Spec]
| TIME_THRESHOLD on pin ZIV33M is "CMOS" :
| Rising=50.0% of vddiom   Falling=50.0% of vddiom
Vinl 697.50000mV 620.50000mV 783.50000mV
Vinh 1.08850V 957.50000mV 1.19550V
| variable   typ   min   max
[Temperature Range] 25.0 140.0 -40.0
| variable   typ   min   max
[Voltage Range] 1.8V 1.6V 2.0V
| variable   typ   min   max
[POWER Clamp Reference] 1.8V 1.6V 2.0V
| variable   typ   min   max
[GND Clamp Reference] 0V 0V 0V
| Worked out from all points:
|   slope of the pulldown table from 0 to 0.27 V, typ, clamps not added: 21.9 ohm
|   slope of the pullup table from 0 to 0.27 V, typ, clamps not added: 22.7 ohm
|   GND clamp passes 1 mA (typ) near -0.51 V on its own axis
|   POWER clamp passes 1 mA (typ) near -0.83 V on its own axis
|   rising waveform, R_fixture 50.0, V_fixture 1.8V: 20-80 % time 334ps typ, 694ps min, 241ps max; typ from 0.654 V to 1.8 V
|   falling waveform, R_fixture 50.0, V_fixture 1.8V: 20-80 % time 3.9ns typ, 5.98ns min, 2.73ns max; typ from 1.8 V to 0.654 V
|   rising waveform, R_fixture 50.0, V_fixture 0V: 20-80 % time 3.47ns typ, 5.85ns min, 2.73ns max; typ from 0 V to 1.16 V
|   falling waveform, R_fixture 50.0, V_fixture 0V: 20-80 % time 1.72ns typ, 2.5ns min, 1.25ns max; typ from 1.16 V to 0 V
[POWER Clamp]
-1.8V     396.4mA    285.5mA    556.9mA
-1.09V    69.42mA    75.17mA    67.14mA
-1.08V    65.31mA    72.42mA    61.23mA
-1.06V    57.23mA    66.98mA    49.77mA
-1.02V    41.75mA    56.3mA     28.91mA
-980mV    27.6mA     45.97mA    12.6mA
-940mV    15.59mA    36.11mA    3.485mA
-880mV    4.091mA    22.61mA    262.5uA
-820mV    594.6uA    11.56mA    16.39uA
-760mV    69.41uA    4.321mA    1.008uA
-630mV    611.2nA    197uA      2.486nA
3.6V      0A         0A         0A
[GND Clamp]
-1.8V     -1.583A    -1.82A     -1.468A
-1.43V    -953.9mA   -1.191A    -839.3mA
-1.24V    -630.9mA   -867.8mA   -516.3mA
-1.05V    -307.9mA   -544.8mA   -193.3mA
-980mV    -188.9mA   -425.8mA   -74.3mA
-950mV    -137.9mA   -374.8mA   -41.62mA
-890mV    -44.57mA   -272.8mA   -24.11mA
-800mV    -13.55mA   -119.8mA   -15.31mA
-760mV    -10.3mA    -56.67mA   -12.19mA
-720mV    -7.957mA   -26.08mA   -9.381mA
-540mV    -1.564mA   -2.435mA   -1.367mA
3.6V      1.281nA    268nA      531.2pA
| variable   typ   min   max
[Pullup Reference] 1.8V 1.6V 2.0V
| variable   typ   min   max
[Pulldown Reference] 0V 0V 0V
[Pullup]
-1.8V     40.39mA    25.65mA    53.38mA
-840mV    39.68mA    25.65mA    53.38mA
-700mV    38.65mA    23.91mA    52.44mA
-560mV    32.65mA    21.17mA    44.13mA
0V        593fA      222.5pA    3.42fA
250mV     -11.21mA   -6.994mA   -16.31mA
440mV     -17.8mA    -11.01mA   -26.16mA
630mV     -22.78mA   -13.92mA   -33.91mA
1V        -28.15mA   -16.69mA   -43.34mA
1.18V     -29.09mA   -17.06mA   -45.52mA
1.6V      -29.9mA    -17.4mA    -47.4mA
3.6V      -30.74mA   -17.73mA   -49.13mA
[Pulldown]
-1.8V     -42.97mA   -20.34mA   -65.35mA
-940mV    -42.97mA   -20.34mA   -65.31mA
-780mV    -41.3mA    -20.34mA   -60.25mA
-650mV    -36.58mA   -20.1mA    -53.93mA
-530mV    -30.86mA   -17.55mA   -45.89mA
0V        1fA        10fA       -3.6fA
250mV     11.67mA    6.208mA    19.03mA
460mV     18.64mA    9.755mA    30.89mA
630mV     22.5mA     11.58mA    37.88mA
810mV     24.97mA    12.61mA    42.87mA
1.18V     26.28mA    13mA       46.33mA
3.6V      27.7mA     13.84mA    48.79mA
[Ramp]
dV/dt_r 693.10984mV/3.39634ns 472.14697mV/5.56437ns 888.79225mV/2.72639ns
dV/dt_f 687.69292mV/3.75036ns 386.84647mV/5.73801ns 924.86466mV/2.72539ns
R_load = 50.0
| Removed startup time: 0s 0s 0s  .
| Removed end time: 35.4ns.
[Rising Waveform]
R_fixture   = 50.0
V_fixture   = 1.8V
V_fixture_min = 1.6V
V_fixture_max = 2.0V
0s        653.8mV    955.3mV    458.6mV
5.8ns     653.8mV    955.3mV    479.3mV
6.1ns     653.8mV    955.3mV    740.4mV
6.45ns    653.8mV    955.3mV    1.859V
7.25ns    653.9mV    955.3mV    1.99V
9ns       728.3mV    955.3mV    1.997V
10.15ns   1.785V     955.3mV    1.998V
15.9ns    1.799V     957.7mV    2V
18.1ns    1.8V       1.592V     2V
35.4ns    1.8V       1.6V       2V
| Removed startup time: 0s 0s 0s  .
| Removed end time: 198.4ns.
[Falling Waveform]
R_fixture   = 50.0
V_fixture   = 1.8V
V_fixture_min = 1.6V
V_fixture_max = 2.0V
0s        1.8V       1.6V       2V
8.55ns    1.8V       1.6V       2.001V
9.75ns    1.804V     1.6V       1.768V
12.95ns   1.72V      1.6V       724.6mV
14.3ns    1.516V     1.6V       594.7mV
17.25ns   938.9mV    1.603V     508mV
20.25ns   753.7mV    1.601V     479.6mV
27.5ns    669.4mV    1.118V     461.9mV
36.45ns   655.8mV    979.6mV    458.9mV
198.4ns   653.8mV    955.3mV    458.6mV
| Removed startup time: 0s 0s 0s  .
| Removed end time: 198.35ns.
[Rising Waveform]
R_fixture   = 50.0
V_fixture   = 0V
V_fixture_min = 0V
V_fixture_max = 0V
0s        4.761nV    149.3nV    3.499nV
7ns       2.949uV    148.3nV    11.34mV
8.1ns     171.5uV    147.5nV    234.2mV
10.3ns    11.99mV    133.5nV    980.3mV
12.15ns   329.1mV    2.658uV    1.343V
16.2ns    1.028V     -3.919mV   1.463V
20.25ns   1.135V     154.8mV    1.478V
25.1ns    1.153V     588.6mV    1.481V
32.4ns    1.155V     768mV      1.481V
198.3ns   1.155V     786.9mV    1.481V
| Removed startup time: 0s 0s 0s  .
| Removed end time: 35.35ns.
[Falling Waveform]
R_fixture   = 50.0
V_fixture   = 0V
V_fixture_min = 0V
V_fixture_max = 0V
0s        1.155V     786.9mV    1.481V
6ns       1.155V     786.9mV    1.478V
6.65ns    1.155V     786.9mV    1.269V
8.2ns     1.155V     786.9mV    206.8mV
9.05ns    1.137V     786.9mV    13.33mV
11.25ns   288mV      786.9mV    1.186mV
13ns      5.74mV     786.9mV    651.3uV
16.55ns   819.1uV    787.1mV    266.7uV
21.65ns   228.2uV    11.97mV    78.07uV
35.35ns   10.57uV    195.3uV    2.436uV
